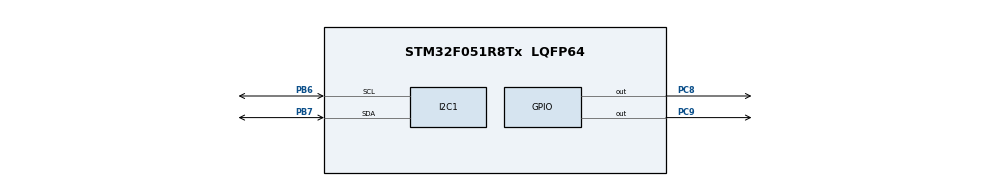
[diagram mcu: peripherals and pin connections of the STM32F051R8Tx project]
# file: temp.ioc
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Mcu.Family=STM32F0
Mcu.Name=STM32F051R8Tx
Mcu.Package=LQFP64
PB6.Mode=I2C
PB6.Signal=I2C1_SCL
PB7.Mode=I2C
PB7.Signal=I2C1_SDA
PC8.Signal=GPIO_Output
PC9.Signal=GPIO_Output
ProjectManager.HeapSize=0x200
ProjectManager.StackSize=0x400
ProjectManager.TargetToolchain=MDK-ARM V5
RCC.AHBFreq_Value=48000000
RCC.APB1Freq_Value=48000000
RCC.APB1TimFreq_Value=48000000
RCC.HCLKFreq_Value=48000000
RCC.PLLMUL=RCC_PLL_MUL12
RCC.SYSCLKFreq_VALUE=48000000
RCC.SYSCLKSource=RCC_SYSCLKSOURCE_PLLCLK
board=custom

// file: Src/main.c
#include "main.h"
#include "stm32f0xx_hal.h"
#include "i2c-lcd.h"
#include "bsp_dht11.h"
I2C_HandleTypeDef hi2c1;

void SystemClock_Config(void);
static void MX_GPIO_Init(void);
static void MX_I2C1_Init(void);

int main(void)
{

	DHT11_DATA_TypeDef DHT11_DATA ;
  	HAL_Init();
	HAL_GPIO_WritePin(GPIOC,GPIO_PIN_9,GPIO_PIN_RESET);
  	SystemClock_Config();
	lcd_init();
  	MX_GPIO_Init();
  	MX_I2C1_Init();
	HAL_Delay(1000);
	DHT11_Init();
	HAL_Delay(50);

  while (1)
{
	if(Read_TempAndHumidity ( & DHT11_DATA)==SUCCESS)
		{
		lcd_goto_XY(1,1);
		lcd_send_string("nhiet do: ");
		HAL_GPIO_WritePin(GPIOC,GPIO_PIN_9,GPIO_PIN_SET);
		}
	else{
		lcd_goto_XY(2,1);
		lcd_send_string("ERROR...");
		HAL_GPIO_WritePin(GPIOC,GPIO_PIN_9,GPIO_PIN_RESET);
		}
	HAL_Delay(1000);
	}
}

void SystemClock_Config(void)
{
  RCC_OscInitTypeDef RCC_OscInitStruct = {0};
  RCC_ClkInitTypeDef RCC_ClkInitStruct = {0};
  RCC_PeriphCLKInitTypeDef PeriphClkInit = {0};
  __HAL_RCC_PWR_CLK_ENABLE();
  RCC_OscInitStruct.OscillatorType = RCC_OSCILLATORTYPE_HSI;
  RCC_OscInitStruct.HSIState = RCC_HSI_ON;
  RCC_OscInitStruct.HSICalibrationValue = RCC_HSICALIBRATION_DEFAULT;
  RCC_OscInitStruct.PLL.PLLState = RCC_PLL_ON;
  RCC_OscInitStruct.PLL.PLLSource = RCC_PLLSOURCE_HSI;
  RCC_OscInitStruct.PLL.PLLMUL = RCC_PLL_MUL12;
  RCC_OscInitStruct.PLL.PREDIV = RCC_PREDIV_DIV1;
  if (HAL_RCC_OscConfig(&RCC_OscInitStruct) != HAL_OK)
  {
    Error_Handler();
  }
  RCC_ClkInitStruct.ClockType = RCC_CLOCKTYPE_HCLK|RCC_CLOCKTYPE_SYSCLK
                              |RCC_CLOCKTYPE_PCLK1;
  RCC_ClkInitStruct.SYSCLKSource = RCC_SYSCLKSOURCE_HSI;
  RCC_ClkInitStruct.AHBCLKDivider = RCC_SYSCLK_DIV1;
  RCC_ClkInitStruct.APB1CLKDivider = RCC_HCLK_DIV1;

  if (HAL_RCC_ClockConfig(&RCC_ClkInitStruct, FLASH_LATENCY_0) != HAL_OK)
  {
    Error_Handler();
  }
  PeriphClkInit.PeriphClockSelection = RCC_PERIPHCLK_I2C1;
  PeriphClkInit.I2c1ClockSelection = RCC_I2C1CLKSOURCE_HSI;
  if (HAL_RCCEx_PeriphCLKConfig(&PeriphClkInit) != HAL_OK)
  {
    Error_Handler();
  }
	HAL_SYSTICK_Config(HAL_RCC_GetHCLKFreq()/1000);

  HAL_SYSTICK_CLKSourceConfig(SYSTICK_CLKSOURCE_HCLK);

  HAL_NVIC_SetPriority(SysTick_IRQn, 0, 0);
}
static void MX_I2C1_Init(void)
{

  hi2c1.Instance = I2C1;
  hi2c1.Init.Timing = 0x2000090E;
  hi2c1.Init.OwnAddress1 = 0;
  hi2c1.Init.AddressingMode = I2C_ADDRESSINGMODE_7BIT;
  hi2c1.Init.DualAddressMode = I2C_DUALADDRESS_DISABLE;
  hi2c1.Init.OwnAddress2 = 0;
  hi2c1.Init.OwnAddress2Masks = I2C_OA2_NOMASK;
  hi2c1.Init.GeneralCallMode = I2C_GENERALCALL_DISABLE;
  hi2c1.Init.NoStretchMode = I2C_NOSTRETCH_DISABLE;
  if (HAL_I2C_Init(&hi2c1) != HAL_OK)
  {
    Error_Handler();
  }
  /**Configure Analogue filter
  */
  if (HAL_I2CEx_ConfigAnalogFilter(&hi2c1, I2C_ANALOGFILTER_ENABLE) != HAL_OK)
  {
    Error_Handler();
  }
  /**Configure Digital filter
  */
  if (HAL_I2CEx_ConfigDigitalFilter(&hi2c1, 0) != HAL_OK)
  {
    Error_Handler();
  }
}

static void MX_GPIO_Init(void)
{
  GPIO_InitTypeDef GPIO_InitStruct = {0};

  /* GPIO Ports Clock Enable */
  __HAL_RCC_GPIOC_CLK_ENABLE();
  __HAL_RCC_GPIOB_CLK_ENABLE();

  /*Configure GPIO pin Output Level */
  HAL_GPIO_WritePin(GPIOC, GPIO_PIN_8|GPIO_PIN_9, GPIO_PIN_RESET);

  /*Configure GPIO pins : PC8 PC9 */
  GPIO_InitStruct.Pin = GPIO_PIN_8|GPIO_PIN_9;
  GPIO_InitStruct.Mode = GPIO_MODE_OUTPUT_PP;
//  GPIO_InitStruct.Pull = GPIO_NOPULL;
	GPIO_InitStruct.Pull = GPIO_PULLUP;
  GPIO_InitStruct.Speed = GPIO_SPEED_FREQ_HIGH;
  HAL_GPIO_Init(GPIOC, &GPIO_InitStruct);

}

void Error_Handler(void)
{
}

/************************ (C) COPYRIGHT STMicroelectronics *****END OF FILE****/
